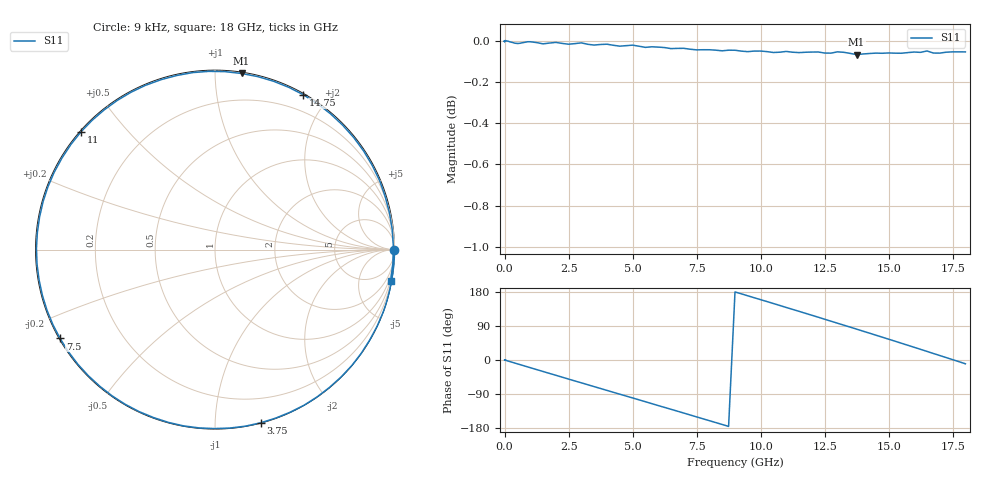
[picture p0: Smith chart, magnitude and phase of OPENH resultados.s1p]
#	HZ	S	MA	R	50.00
! Rohde & Schwarz Vector Network Analyzer
! Rohde-Schwarz,ZNB43-2Port,1334333092101683,4.21
! Created: UTC 09/15/2026, 11:47:42 AM
! freq[Hz]	mag:S12	ang:S12
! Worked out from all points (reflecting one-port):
!   116 points, 9 kHz to 18 GHz, reference 50 ohm
!   lowest |S11| = -0.1 dB at 13.75 GHz (marker M1), VSWR 262.30, Z = 0.448 + j58.1 ohm
!   phase of S11 starts at -0 deg and turns -370 deg over the sweep
!   S11 on the Smith chart (normalised r, x): 9 kHz: open; 3.75 GHz: 0.00, -1.30; 7.5 GHz: 0.00, -0.27; 11 GHz: 0.00, +0.38; 14.75 GHz: 0.01, +1.72; 18 GHz: 0, -11
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9000  0.9999 -0.0
4e7  1 0.4
5e7  1 -1.0
7e8  0.9991 -14.2
1.25e9  0.9991 -25.3
2e9  0.9992 -40.3
2.5e9  0.9982 -50.4
3e9  0.999 -60.3
3.75e9  0.9981 -75.3
4.75e9  0.9974 -95.2
5.75e9  0.9968 -115.1
6.25e9  0.9963 -125.1
7e9  0.9959 -140.1
7.5e9  0.9951 -150.2
8.5e9  0.9945 -170.2
9.25e9  0.9943 174.5
1e10  0.9944 159.3
1.1e10  0.9942 138.7
1.15e10  0.9935 128.5
1.225e10  0.9939 112.9
1.275e10  0.9932 102.4
1.375e10  0.9924 81.4
1.475e10  0.9932 60.3
1.525e10  0.9932 49.7
1.6e10  0.9938 33.5
1.7e10  0.9932 11.8
1.75e10  0.9939 1.0
1.8e10  0.9939 -10.0
